VERSION 5.7 ;
BUSBITCHARS "[]" ;
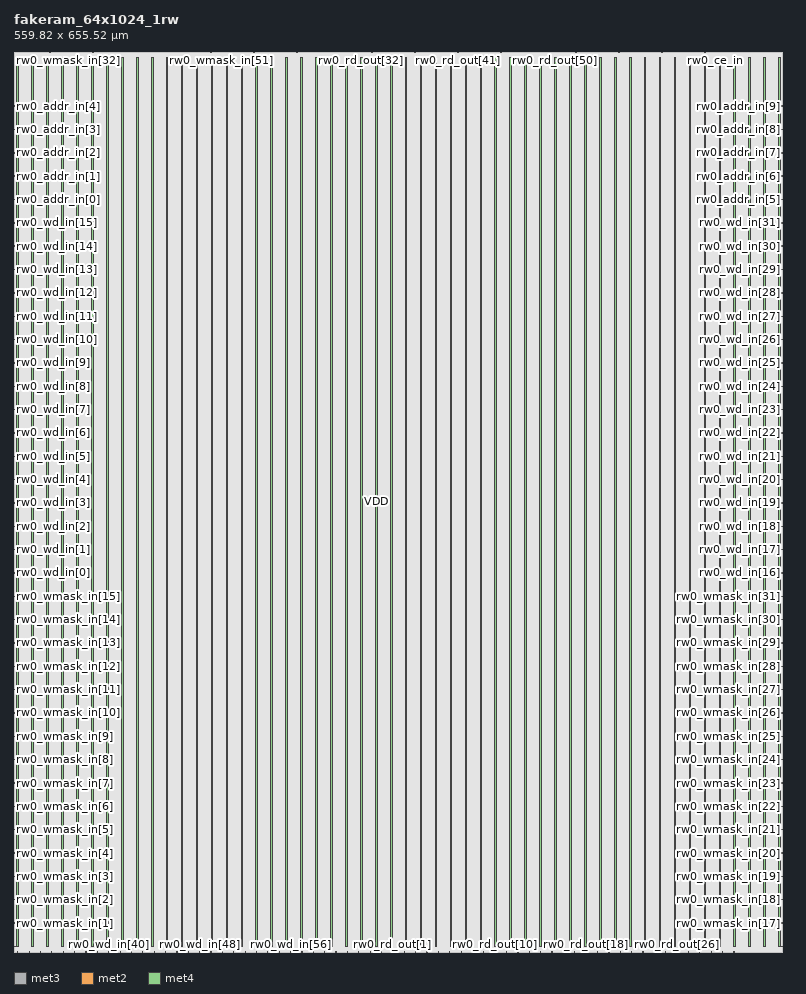
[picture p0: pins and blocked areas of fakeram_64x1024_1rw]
MACRO fakeram_64x1024_1rw
  FOREIGN fakeram_64x1024_1rw 0 0 ;
  SYMMETRY X Y R90 ;
  SIZE 559.820 BY 655.520 ;
  CLASS BLOCK ;
  PIN rw0_wmask_in[0]
    DIRECTION INPUT ;
    USE SIGNAL ;
    SHAPE ABUTMENT ;
    PORT
      LAYER met3 ;
      RECT 0.000 3.930 0.900 4.230 ;
    END
  END rw0_wmask_in[0]
  PIN rw0_wmask_in[1]
    DIRECTION INPUT ;
    USE SIGNAL ;
    SHAPE ABUTMENT ;
    PORT
      LAYER met3 ;
      RECT 0.000 20.930 0.900 21.230 ;
    END
  END rw0_wmask_in[1]
  PIN rw0_wmask_in[2]
    DIRECTION INPUT ;
    USE SIGNAL ;
    SHAPE ABUTMENT ;
    PORT
      LAYER met3 ;
      RECT 0.000 37.930 0.900 38.230 ;
    END
  END rw0_wmask_in[2]
  PIN rw0_wmask_in[3]
    DIRECTION INPUT ;
    USE SIGNAL ;
    SHAPE ABUTMENT ;
    PORT
      LAYER met3 ;
      RECT 0.000 54.930 0.900 55.230 ;
    END
  END rw0_wmask_in[3]
  PIN rw0_wmask_in[4]
    DIRECTION INPUT ;
    USE SIGNAL ;
    SHAPE ABUTMENT ;
    PORT
      LAYER met3 ;
      RECT 0.000 71.930 0.900 72.230 ;
    END
  END rw0_wmask_in[4]
  PIN rw0_wmask_in[5]
    DIRECTION INPUT ;
    USE SIGNAL ;
    SHAPE ABUTMENT ;
    PORT
      LAYER met3 ;
      RECT 0.000 88.930 0.900 89.230 ;
    END
  END rw0_wmask_in[5]
  PIN rw0_wmask_in[6]
    DIRECTION INPUT ;
    USE SIGNAL ;
    SHAPE ABUTMENT ;
    PORT
      LAYER met3 ;
      RECT 0.000 105.930 0.900 106.230 ;
    END
  END rw0_wmask_in[6]
  PIN rw0_wmask_in[7]
    DIRECTION INPUT ;
    USE SIGNAL ;
    SHAPE ABUTMENT ;
    PORT
      LAYER met3 ;
      RECT 0.000 122.930 0.900 123.230 ;
    END
  END rw0_wmask_in[7]
  PIN rw0_wmask_in[8]
    DIRECTION INPUT ;
    USE SIGNAL ;
    SHAPE ABUTMENT ;
    PORT
      LAYER met3 ;
      RECT 0.000 139.930 0.900 140.230 ;
    END
  END rw0_wmask_in[8]
  PIN rw0_wmask_in[9]
    DIRECTION INPUT ;
    USE SIGNAL ;
    SHAPE ABUTMENT ;
    PORT
      LAYER met3 ;
      RECT 0.000 156.930 0.900 157.230 ;
    END
  END rw0_wmask_in[9]
  PIN rw0_wmask_in[10]
    DIRECTION INPUT ;
    USE SIGNAL ;
    SHAPE ABUTMENT ;
    PORT
      LAYER met3 ;
      RECT 0.000 173.930 0.900 174.230 ;
    END
  END rw0_wmask_in[10]
  PIN rw0_wmask_in[11]
    DIRECTION INPUT ;
    USE SIGNAL ;
    SHAPE ABUTMENT ;
    PORT
      LAYER met3 ;
      RECT 0.000 190.930 0.900 191.230 ;
    END
  END rw0_wmask_in[11]
  PIN rw0_wmask_in[12]
    DIRECTION INPUT ;
    USE SIGNAL ;
    SHAPE ABUTMENT ;
    PORT
      LAYER met3 ;
      RECT 0.000 207.930 0.900 208.230 ;
    END
  END rw0_wmask_in[12]
  PIN rw0_wmask_in[13]
    DIRECTION INPUT ;
    USE SIGNAL ;
    SHAPE ABUTMENT ;
    PORT
      LAYER met3 ;
      RECT 0.000 224.930 0.900 225.230 ;
    END
  END rw0_wmask_in[13]
  PIN rw0_wmask_in[14]
    DIRECTION INPUT ;
    USE SIGNAL ;
    SHAPE ABUTMENT ;
    PORT
      LAYER met3 ;
      RECT 0.000 241.930 0.900 242.230 ;
    END
  END rw0_wmask_in[14]
  PIN rw0_wmask_in[15]
    DIRECTION INPUT ;
    USE SIGNAL ;
    SHAPE ABUTMENT ;
    PORT
      LAYER met3 ;
      RECT 0.000 258.930 0.900 259.230 ;
    END
  END rw0_wmask_in[15]
  PIN rw0_wmask_in[16]
    DIRECTION INPUT ;
    USE SIGNAL ;
    SHAPE ABUTMENT ;
    PORT
      LAYER met3 ;
      RECT 558.920 3.930 559.820 4.230 ;
    END
  END rw0_wmask_in[16]
  PIN rw0_wmask_in[17]
    DIRECTION INPUT ;
    USE SIGNAL ;
    SHAPE ABUTMENT ;
    PORT
      LAYER met3 ;
      RECT 558.920 20.930 559.820 21.230 ;
    END
  END rw0_wmask_in[17]
  PIN rw0_wmask_in[18]
    DIRECTION INPUT ;
    USE SIGNAL ;
    SHAPE ABUTMENT ;
    PORT
      LAYER met3 ;
      RECT 558.920 37.930 559.820 38.230 ;
    END
  END rw0_wmask_in[18]
  PIN rw0_wmask_in[19]
    DIRECTION INPUT ;
    USE SIGNAL ;
    SHAPE ABUTMENT ;
    PORT
      LAYER met3 ;
      RECT 558.920 54.930 559.820 55.230 ;
    END
  END rw0_wmask_in[19]
  PIN rw0_wmask_in[20]
    DIRECTION INPUT ;
    USE SIGNAL ;
    SHAPE ABUTMENT ;
    PORT
      LAYER met3 ;
      RECT 558.920 71.930 559.820 72.230 ;
    END
  END rw0_wmask_in[20]
  PIN rw0_wmask_in[21]
    DIRECTION INPUT ;
    USE SIGNAL ;
    SHAPE ABUTMENT ;
    PORT
      LAYER met3 ;
      RECT 558.920 88.930 559.820 89.230 ;
    END
  END rw0_wmask_in[21]
  PIN rw0_wmask_in[22]
    DIRECTION INPUT ;
    USE SIGNAL ;
    SHAPE ABUTMENT ;
    PORT
      LAYER met3 ;
      RECT 558.920 105.930 559.820 106.230 ;
    END
  END rw0_wmask_in[22]
  PIN rw0_wmask_in[23]
    DIRECTION INPUT ;
    USE SIGNAL ;
    SHAPE ABUTMENT ;
    PORT
      LAYER met3 ;
      RECT 558.920 122.930 559.820 123.230 ;
    END
  END rw0_wmask_in[23]
  PIN rw0_wmask_in[24]
    DIRECTION INPUT ;
    USE SIGNAL ;
    SHAPE ABUTMENT ;
    PORT
      LAYER met3 ;
      RECT 558.920 139.930 559.820 140.230 ;
    END
  END rw0_wmask_in[24]
  PIN rw0_wmask_in[25]
    DIRECTION INPUT ;
    USE SIGNAL ;
    SHAPE ABUTMENT ;
    PORT
      LAYER met3 ;
      RECT 558.920 156.930 559.820 157.230 ;
    END
  END rw0_wmask_in[25]
  PIN rw0_wmask_in[26]
    DIRECTION INPUT ;
    USE SIGNAL ;
    SHAPE ABUTMENT ;
    PORT
      LAYER met3 ;
      RECT 558.920 173.930 559.820 174.230 ;
    END
  END rw0_wmask_in[26]
  PIN rw0_wmask_in[27]
    DIRECTION INPUT ;
    USE SIGNAL ;
    SHAPE ABUTMENT ;
    PORT
      LAYER met3 ;
      RECT 558.920 190.930 559.820 191.230 ;
    END
  END rw0_wmask_in[27]
  PIN rw0_wmask_in[28]
    DIRECTION INPUT ;
    USE SIGNAL ;
    SHAPE ABUTMENT ;
    PORT
      LAYER met3 ;
      RECT 558.920 207.930 559.820 208.230 ;
    END
  END rw0_wmask_in[28]
  PIN rw0_wmask_in[29]
    DIRECTION INPUT ;
    USE SIGNAL ;
    SHAPE ABUTMENT ;
    PORT
      LAYER met3 ;
      RECT 558.920 224.930 559.820 225.230 ;
    END
  END rw0_wmask_in[29]
  PIN rw0_wmask_in[30]
    DIRECTION INPUT ;
    USE SIGNAL ;
    SHAPE ABUTMENT ;
    PORT
      LAYER met3 ;
      RECT 558.920 241.930 559.820 242.230 ;
    END
  END rw0_wmask_in[30]
  PIN rw0_wmask_in[31]
    DIRECTION INPUT ;
    USE SIGNAL ;
    SHAPE ABUTMENT ;
    PORT
      LAYER met3 ;
      RECT 558.920 258.930 559.820 259.230 ;
    END
  END rw0_wmask_in[31]
  PIN rw0_wmask_in[32]
    DIRECTION INPUT ;
    USE SIGNAL ;
    SHAPE ABUTMENT ;
    PORT
      LAYER met2 ;
      RECT 2.690 655.100 2.830 655.520 ;
    END
  END rw0_wmask_in[32]
  PIN rw0_wmask_in[33]
    DIRECTION INPUT ;
    USE SIGNAL ;
    SHAPE ABUTMENT ;
    PORT
      LAYER met2 ;
      RECT 10.510 655.100 10.650 655.520 ;
    END
  END rw0_wmask_in[33]
  PIN rw0_wmask_in[34]
    DIRECTION INPUT ;
    USE SIGNAL ;
    SHAPE ABUTMENT ;
    PORT
      LAYER met2 ;
      RECT 18.330 655.100 18.470 655.520 ;
    END
  END rw0_wmask_in[34]
  PIN rw0_wmask_in[35]
    DIRECTION INPUT ;
    USE SIGNAL ;
    SHAPE ABUTMENT ;
    PORT
      LAYER met2 ;
      RECT 26.150 655.100 26.290 655.520 ;
    END
  END rw0_wmask_in[35]
  PIN rw0_wmask_in[36]
    DIRECTION INPUT ;
    USE SIGNAL ;
    SHAPE ABUTMENT ;
    PORT
      LAYER met2 ;
      RECT 33.970 655.100 34.110 655.520 ;
    END
  END rw0_wmask_in[36]
  PIN rw0_wmask_in[37]
    DIRECTION INPUT ;
    USE SIGNAL ;
    SHAPE ABUTMENT ;
    PORT
      LAYER met2 ;
      RECT 41.790 655.100 41.930 655.520 ;
    END
  END rw0_wmask_in[37]
  PIN rw0_wmask_in[38]
    DIRECTION INPUT ;
    USE SIGNAL ;
    SHAPE ABUTMENT ;
    PORT
      LAYER met2 ;
      RECT 49.610 655.100 49.750 655.520 ;
    END
  END rw0_wmask_in[38]
  PIN rw0_wmask_in[39]
    DIRECTION INPUT ;
    USE SIGNAL ;
    SHAPE ABUTMENT ;
    PORT
      LAYER met2 ;
      RECT 57.430 655.100 57.570 655.520 ;
    END
  END rw0_wmask_in[39]
  PIN rw0_wmask_in[40]
    DIRECTION INPUT ;
    USE SIGNAL ;
    SHAPE ABUTMENT ;
    PORT
      LAYER met2 ;
      RECT 65.250 655.100 65.390 655.520 ;
    END
  END rw0_wmask_in[40]
  PIN rw0_wmask_in[41]
    DIRECTION INPUT ;
    USE SIGNAL ;
    SHAPE ABUTMENT ;
    PORT
      LAYER met2 ;
      RECT 73.070 655.100 73.210 655.520 ;
    END
  END rw0_wmask_in[41]
  PIN rw0_wmask_in[42]
    DIRECTION INPUT ;
    USE SIGNAL ;
    SHAPE ABUTMENT ;
    PORT
      LAYER met2 ;
      RECT 80.890 655.100 81.030 655.520 ;
    END
  END rw0_wmask_in[42]
  PIN rw0_wmask_in[43]
    DIRECTION INPUT ;
    USE SIGNAL ;
    SHAPE ABUTMENT ;
    PORT
      LAYER met2 ;
      RECT 88.710 655.100 88.850 655.520 ;
    END
  END rw0_wmask_in[43]
  PIN rw0_wmask_in[44]
    DIRECTION INPUT ;
    USE SIGNAL ;
    SHAPE ABUTMENT ;
    PORT
      LAYER met2 ;
      RECT 96.530 655.100 96.670 655.520 ;
    END
  END rw0_wmask_in[44]
  PIN rw0_wmask_in[45]
    DIRECTION INPUT ;
    USE SIGNAL ;
    SHAPE ABUTMENT ;
    PORT
      LAYER met2 ;
      RECT 104.350 655.100 104.490 655.520 ;
    END
  END rw0_wmask_in[45]
  PIN rw0_wmask_in[46]
    DIRECTION INPUT ;
    USE SIGNAL ;
    SHAPE ABUTMENT ;
    PORT
      LAYER met2 ;
      RECT 112.170 655.100 112.310 655.520 ;
    END
  END rw0_wmask_in[46]
  PIN rw0_wmask_in[47]
    DIRECTION INPUT ;
    USE SIGNAL ;
    SHAPE ABUTMENT ;
    PORT
      LAYER met2 ;
      RECT 119.990 655.100 120.130 655.520 ;
    END
  END rw0_wmask_in[47]
  PIN rw0_wmask_in[48]
    DIRECTION INPUT ;
    USE SIGNAL ;
    SHAPE ABUTMENT ;
    PORT
      LAYER met2 ;
      RECT 127.810 655.100 127.950 655.520 ;
    END
  END rw0_wmask_in[48]
  PIN rw0_wmask_in[49]
    DIRECTION INPUT ;
    USE SIGNAL ;
    SHAPE ABUTMENT ;
    PORT
      LAYER met2 ;
      RECT 135.630 655.100 135.770 655.520 ;
    END
  END rw0_wmask_in[49]
  PIN rw0_wmask_in[50]
    DIRECTION INPUT ;
    USE SIGNAL ;
    SHAPE ABUTMENT ;
    PORT
      LAYER met2 ;
      RECT 143.450 655.100 143.590 655.520 ;
    END
  END rw0_wmask_in[50]
  PIN rw0_wmask_in[51]
    DIRECTION INPUT ;
    USE SIGNAL ;
    SHAPE ABUTMENT ;
    PORT
      LAYER met2 ;
      RECT 151.270 655.100 151.410 655.520 ;
    END
  END rw0_wmask_in[51]
  PIN rw0_wmask_in[52]
    DIRECTION INPUT ;
    USE SIGNAL ;
    SHAPE ABUTMENT ;
    PORT
      LAYER met2 ;
      RECT 159.090 655.100 159.230 655.520 ;
    END
  END rw0_wmask_in[52]
  PIN rw0_wmask_in[53]
    DIRECTION INPUT ;
    USE SIGNAL ;
    SHAPE ABUTMENT ;
    PORT
      LAYER met2 ;
      RECT 166.910 655.100 167.050 655.520 ;
    END
  END rw0_wmask_in[53]
  PIN rw0_wmask_in[54]
    DIRECTION INPUT ;
    USE SIGNAL ;
    SHAPE ABUTMENT ;
    PORT
      LAYER met2 ;
      RECT 174.730 655.100 174.870 655.520 ;
    END
  END rw0_wmask_in[54]
  PIN rw0_wmask_in[55]
    DIRECTION INPUT ;
    USE SIGNAL ;
    SHAPE ABUTMENT ;
    PORT
      LAYER met2 ;
      RECT 182.550 655.100 182.690 655.520 ;
    END
  END rw0_wmask_in[55]
  PIN rw0_wmask_in[56]
    DIRECTION INPUT ;
    USE SIGNAL ;
    SHAPE ABUTMENT ;
    PORT
      LAYER met2 ;
      RECT 190.370 655.100 190.510 655.520 ;
    END
  END rw0_wmask_in[56]
  PIN rw0_wmask_in[57]
    DIRECTION INPUT ;
    USE SIGNAL ;
    SHAPE ABUTMENT ;
    PORT
      LAYER met2 ;
      RECT 198.190 655.100 198.330 655.520 ;
    END
  END rw0_wmask_in[57]
  PIN rw0_wmask_in[58]
    DIRECTION INPUT ;
    USE SIGNAL ;
    SHAPE ABUTMENT ;
    PORT
      LAYER met2 ;
      RECT 206.010 655.100 206.150 655.520 ;
    END
  END rw0_wmask_in[58]
  PIN rw0_wmask_in[59]
    DIRECTION INPUT ;
    USE SIGNAL ;
    SHAPE ABUTMENT ;
    PORT
      LAYER met2 ;
      RECT 213.830 655.100 213.970 655.520 ;
    END
  END rw0_wmask_in[59]
  PIN rw0_wmask_in[60]
    DIRECTION INPUT ;
    USE SIGNAL ;
    SHAPE ABUTMENT ;
    PORT
      LAYER met2 ;
      RECT 221.650 655.100 221.790 655.520 ;
    END
  END rw0_wmask_in[60]
  PIN rw0_wmask_in[61]
    DIRECTION INPUT ;
    USE SIGNAL ;
    SHAPE ABUTMENT ;
    PORT
      LAYER met2 ;
      RECT 229.470 655.100 229.610 655.520 ;
    END
  END rw0_wmask_in[61]
  PIN rw0_wmask_in[62]
    DIRECTION INPUT ;
    USE SIGNAL ;
    SHAPE ABUTMENT ;
    PORT
      LAYER met2 ;
      RECT 237.290 655.100 237.430 655.520 ;
    END
  END rw0_wmask_in[62]
  PIN rw0_wmask_in[63]
    DIRECTION INPUT ;
    USE SIGNAL ;
    SHAPE ABUTMENT ;
    PORT
      LAYER met2 ;
      RECT 245.110 655.100 245.250 655.520 ;
    END
  END rw0_wmask_in[63]
  PIN rw0_wd_in[0]
    DIRECTION INPUT ;
    USE SIGNAL ;
    SHAPE ABUTMENT ;
    PORT
      LAYER met3 ;
      RECT 0.000 275.930 0.900 276.230 ;
    END
  END rw0_wd_in[0]
  PIN rw0_wd_in[1]
    DIRECTION INPUT ;
    USE SIGNAL ;
    SHAPE ABUTMENT ;
    PORT
      LAYER met3 ;
      RECT 0.000 292.930 0.900 293.230 ;
    END
  END rw0_wd_in[1]
  PIN rw0_wd_in[2]
    DIRECTION INPUT ;
    USE SIGNAL ;
    SHAPE ABUTMENT ;
    PORT
      LAYER met3 ;
      RECT 0.000 309.930 0.900 310.230 ;
    END
  END rw0_wd_in[2]
  PIN rw0_wd_in[3]
    DIRECTION INPUT ;
    USE SIGNAL ;
    SHAPE ABUTMENT ;
    PORT
      LAYER met3 ;
      RECT 0.000 326.930 0.900 327.230 ;
    END
  END rw0_wd_in[3]
  PIN rw0_wd_in[4]
    DIRECTION INPUT ;
    USE SIGNAL ;
    SHAPE ABUTMENT ;
    PORT
      LAYER met3 ;
      RECT 0.000 343.930 0.900 344.230 ;
    END
  END rw0_wd_in[4]
  PIN rw0_wd_in[5]
    DIRECTION INPUT ;
    USE SIGNAL ;
    SHAPE ABUTMENT ;
    PORT
      LAYER met3 ;
      RECT 0.000 360.930 0.900 361.230 ;
    END
  END rw0_wd_in[5]
  PIN rw0_wd_in[6]
    DIRECTION INPUT ;
    USE SIGNAL ;
    SHAPE ABUTMENT ;
    PORT
      LAYER met3 ;
      RECT 0.000 377.930 0.900 378.230 ;
    END
  END rw0_wd_in[6]
  PIN rw0_wd_in[7]
    DIRECTION INPUT ;
    USE SIGNAL ;
    SHAPE ABUTMENT ;
    PORT
      LAYER met3 ;
      RECT 0.000 394.930 0.900 395.230 ;
    END
  END rw0_wd_in[7]
  PIN rw0_wd_in[8]
    DIRECTION INPUT ;
    USE SIGNAL ;
    SHAPE ABUTMENT ;
    PORT
      LAYER met3 ;
      RECT 0.000 411.930 0.900 412.230 ;
    END
  END rw0_wd_in[8]
  PIN rw0_wd_in[9]
    DIRECTION INPUT ;
    USE SIGNAL ;
    SHAPE ABUTMENT ;
    PORT
      LAYER met3 ;
      RECT 0.000 428.930 0.900 429.230 ;
    END
  END rw0_wd_in[9]
  PIN rw0_wd_in[10]
    DIRECTION INPUT ;
    USE SIGNAL ;
    SHAPE ABUTMENT ;
    PORT
      LAYER met3 ;
      RECT 0.000 445.930 0.900 446.230 ;
    END
  END rw0_wd_in[10]
  PIN rw0_wd_in[11]
    DIRECTION INPUT ;
    USE SIGNAL ;
    SHAPE ABUTMENT ;
    PORT
      LAYER met3 ;
      RECT 0.000 462.930 0.900 463.230 ;
    END
  END rw0_wd_in[11]
  PIN rw0_wd_in[12]
    DIRECTION INPUT ;
    USE SIGNAL ;
    SHAPE ABUTMENT ;
    PORT
      LAYER met3 ;
      RECT 0.000 479.930 0.900 480.230 ;
    END
  END rw0_wd_in[12]
  PIN rw0_wd_in[13]
    DIRECTION INPUT ;
    USE SIGNAL ;
    SHAPE ABUTMENT ;
    PORT
      LAYER met3 ;
      RECT 0.000 496.930 0.900 497.230 ;
    END
  END rw0_wd_in[13]
  PIN rw0_wd_in[14]
    DIRECTION INPUT ;
    USE SIGNAL ;
    SHAPE ABUTMENT ;
    PORT
      LAYER met3 ;
      RECT 0.000 513.930 0.900 514.230 ;
    END
  END rw0_wd_in[14]
  PIN rw0_wd_in[15]
    DIRECTION INPUT ;
    USE SIGNAL ;
    SHAPE ABUTMENT ;
    PORT
      LAYER met3 ;
      RECT 0.000 530.930 0.900 531.230 ;
    END
  END rw0_wd_in[15]
  PIN rw0_wd_in[16]
    DIRECTION INPUT ;
    USE SIGNAL ;
    SHAPE ABUTMENT ;
    PORT
      LAYER met3 ;
      RECT 558.920 275.930 559.820 276.230 ;
    END
  END rw0_wd_in[16]
  PIN rw0_wd_in[17]
    DIRECTION INPUT ;
    USE SIGNAL ;
    SHAPE ABUTMENT ;
    PORT
      LAYER met3 ;
      RECT 558.920 292.930 559.820 293.230 ;
    END
  END rw0_wd_in[17]
  PIN rw0_wd_in[18]
    DIRECTION INPUT ;
    USE SIGNAL ;
    SHAPE ABUTMENT ;
    PORT
      LAYER met3 ;
      RECT 558.920 309.930 559.820 310.230 ;
    END
  END rw0_wd_in[18]
  PIN rw0_wd_in[19]
    DIRECTION INPUT ;
    USE SIGNAL ;
    SHAPE ABUTMENT ;
    PORT
      LAYER met3 ;
      RECT 558.920 326.930 559.820 327.230 ;
    END
  END rw0_wd_in[19]
  PIN rw0_wd_in[20]
    DIRECTION INPUT ;
    USE SIGNAL ;
    SHAPE ABUTMENT ;
    PORT
      LAYER met3 ;
      RECT 558.920 343.930 559.820 344.230 ;
    END
  END rw0_wd_in[20]
  PIN rw0_wd_in[21]
    DIRECTION INPUT ;
    USE SIGNAL ;
    SHAPE ABUTMENT ;
    PORT
      LAYER met3 ;
      RECT 558.920 360.930 559.820 361.230 ;
    END
  END rw0_wd_in[21]
  PIN rw0_wd_in[22]
    DIRECTION INPUT ;
    USE SIGNAL ;
    SHAPE ABUTMENT ;
    PORT
      LAYER met3 ;
      RECT 558.920 377.930 559.820 378.230 ;
    END
  END rw0_wd_in[22]
  PIN rw0_wd_in[23]
    DIRECTION INPUT ;
    USE SIGNAL ;
    SHAPE ABUTMENT ;
    PORT
      LAYER met3 ;
      RECT 558.920 394.930 559.820 395.230 ;
    END
  END rw0_wd_in[23]
  PIN rw0_wd_in[24]
    DIRECTION INPUT ;
    USE SIGNAL ;
    SHAPE ABUTMENT ;
    PORT
      LAYER met3 ;
      RECT 558.920 411.930 559.820 412.230 ;
    END
  END rw0_wd_in[24]
  PIN rw0_wd_in[25]
    DIRECTION INPUT ;
    USE SIGNAL ;
    SHAPE ABUTMENT ;
    PORT
      LAYER met3 ;
      RECT 558.920 428.930 559.820 429.230 ;
    END
  END rw0_wd_in[25]
  PIN rw0_wd_in[26]
    DIRECTION INPUT ;
    USE SIGNAL ;
    SHAPE ABUTMENT ;
    PORT
      LAYER met3 ;
      RECT 558.920 445.930 559.820 446.230 ;
    END
  END rw0_wd_in[26]
  PIN rw0_wd_in[27]
    DIRECTION INPUT ;
    USE SIGNAL ;
    SHAPE ABUTMENT ;
    PORT
      LAYER met3 ;
      RECT 558.920 462.930 559.820 463.230 ;
    END
  END rw0_wd_in[27]
  PIN rw0_wd_in[28]
    DIRECTION INPUT ;
    USE SIGNAL ;
    SHAPE ABUTMENT ;
    PORT
      LAYER met3 ;
      RECT 558.920 479.930 559.820 480.230 ;
    END
  END rw0_wd_in[28]
  PIN rw0_wd_in[29]
    DIRECTION INPUT ;
    USE SIGNAL ;
    SHAPE ABUTMENT ;
    PORT
      LAYER met3 ;
      RECT 558.920 496.930 559.820 497.230 ;
    END
  END rw0_wd_in[29]
  PIN rw0_wd_in[30]
    DIRECTION INPUT ;
    USE SIGNAL ;
    SHAPE ABUTMENT ;
    PORT
      LAYER met3 ;
      RECT 558.920 513.930 559.820 514.230 ;
    END
  END rw0_wd_in[30]
  PIN rw0_wd_in[31]
    DIRECTION INPUT ;
    USE SIGNAL ;
    SHAPE ABUTMENT ;
    PORT
      LAYER met3 ;
      RECT 558.920 530.930 559.820 531.230 ;
    END
  END rw0_wd_in[31]
  PIN rw0_wd_in[32]
    DIRECTION OUTPUT ;
    USE SIGNAL ;
    SHAPE ABUTMENT ;
    PORT
      LAYER met2 ;
      RECT 2.690 0.000 2.830 0.420 ;
    END
  END rw0_wd_in[32]
  PIN rw0_wd_in[33]
    DIRECTION OUTPUT ;
    USE SIGNAL ;
    SHAPE ABUTMENT ;
    PORT
      LAYER met2 ;
      RECT 10.970 0.000 11.110 0.420 ;
    END
  END rw0_wd_in[33]
  PIN rw0_wd_in[34]
    DIRECTION OUTPUT ;
    USE SIGNAL ;
    SHAPE ABUTMENT ;
    PORT
      LAYER met2 ;
      RECT 19.250 0.000 19.390 0.420 ;
    END
  END rw0_wd_in[34]
  PIN rw0_wd_in[35]
    DIRECTION OUTPUT ;
    USE SIGNAL ;
    SHAPE ABUTMENT ;
    PORT
      LAYER met2 ;
      RECT 27.530 0.000 27.670 0.420 ;
    END
  END rw0_wd_in[35]
  PIN rw0_wd_in[36]
    DIRECTION OUTPUT ;
    USE SIGNAL ;
    SHAPE ABUTMENT ;
    PORT
      LAYER met2 ;
      RECT 35.810 0.000 35.950 0.420 ;
    END
  END rw0_wd_in[36]
  PIN rw0_wd_in[37]
    DIRECTION OUTPUT ;
    USE SIGNAL ;
    SHAPE ABUTMENT ;
    PORT
      LAYER met2 ;
      RECT 44.090 0.000 44.230 0.420 ;
    END
  END rw0_wd_in[37]
  PIN rw0_wd_in[38]
    DIRECTION OUTPUT ;
    USE SIGNAL ;
    SHAPE ABUTMENT ;
    PORT
      LAYER met2 ;
      RECT 52.370 0.000 52.510 0.420 ;
    END
  END rw0_wd_in[38]
  PIN rw0_wd_in[39]
    DIRECTION OUTPUT ;
    USE SIGNAL ;
    SHAPE ABUTMENT ;
    PORT
      LAYER met2 ;
      RECT 60.650 0.000 60.790 0.420 ;
    END
  END rw0_wd_in[39]
  PIN rw0_wd_in[40]
    DIRECTION OUTPUT ;
    USE SIGNAL ;
    SHAPE ABUTMENT ;
    PORT
      LAYER met2 ;
      RECT 68.930 0.000 69.070 0.420 ;
    END
  END rw0_wd_in[40]
  PIN rw0_wd_in[41]
    DIRECTION OUTPUT ;
    USE SIGNAL ;
    SHAPE ABUTMENT ;
    PORT
      LAYER met2 ;
      RECT 77.210 0.000 77.350 0.420 ;
    END
  END rw0_wd_in[41]
  PIN rw0_wd_in[42]
    DIRECTION OUTPUT ;
    USE SIGNAL ;
    SHAPE ABUTMENT ;
    PORT
      LAYER met2 ;
      RECT 85.490 0.000 85.630 0.420 ;
    END
  END rw0_wd_in[42]
  PIN rw0_wd_in[43]
    DIRECTION OUTPUT ;
    USE SIGNAL ;
    SHAPE ABUTMENT ;
    PORT
      LAYER met2 ;
      RECT 93.770 0.000 93.910 0.420 ;
    END
  END rw0_wd_in[43]
  PIN rw0_wd_in[44]
    DIRECTION OUTPUT ;
    USE SIGNAL ;
    SHAPE ABUTMENT ;
    PORT
      LAYER met2 ;
      RECT 102.050 0.000 102.190 0.420 ;
    END
  END rw0_wd_in[44]
  PIN rw0_wd_in[45]
    DIRECTION OUTPUT ;
    USE SIGNAL ;
    SHAPE ABUTMENT ;
    PORT
      LAYER met2 ;
      RECT 110.330 0.000 110.470 0.420 ;
    END
  END rw0_wd_in[45]
  PIN rw0_wd_in[46]
    DIRECTION OUTPUT ;
    USE SIGNAL ;
    SHAPE ABUTMENT ;
    PORT
      LAYER met2 ;
      RECT 118.610 0.000 118.750 0.420 ;
    END
  END rw0_wd_in[46]
  PIN rw0_wd_in[47]
    DIRECTION OUTPUT ;
    USE SIGNAL ;
    SHAPE ABUTMENT ;
    PORT
      LAYER met2 ;
      RECT 126.890 0.000 127.030 0.420 ;
    END
  END rw0_wd_in[47]
  PIN rw0_wd_in[48]
    DIRECTION OUTPUT ;
    USE SIGNAL ;
    SHAPE ABUTMENT ;
    PORT
      LAYER met2 ;
      RECT 135.170 0.000 135.310 0.420 ;
    END
  END rw0_wd_in[48]
  PIN rw0_wd_in[49]
    DIRECTION OUTPUT ;
    USE SIGNAL ;
    SHAPE ABUTMENT ;
    PORT
      LAYER met2 ;
      RECT 143.450 0.000 143.590 0.420 ;
    END
  END rw0_wd_in[49]
  PIN rw0_wd_in[50]
    DIRECTION OUTPUT ;
    USE SIGNAL ;
    SHAPE ABUTMENT ;
    PORT
      LAYER met2 ;
      RECT 151.730 0.000 151.870 0.420 ;
    END
  END rw0_wd_in[50]
  PIN rw0_wd_in[51]
    DIRECTION OUTPUT ;
    USE SIGNAL ;
    SHAPE ABUTMENT ;
    PORT
      LAYER met2 ;
      RECT 160.010 0.000 160.150 0.420 ;
    END
  END rw0_wd_in[51]
  PIN rw0_wd_in[52]
    DIRECTION OUTPUT ;
    USE SIGNAL ;
    SHAPE ABUTMENT ;
    PORT
      LAYER met2 ;
      RECT 168.290 0.000 168.430 0.420 ;
    END
  END rw0_wd_in[52]
  PIN rw0_wd_in[53]
    DIRECTION OUTPUT ;
    USE SIGNAL ;
    SHAPE ABUTMENT ;
    PORT
      LAYER met2 ;
      RECT 176.570 0.000 176.710 0.420 ;
    END
  END rw0_wd_in[53]
  PIN rw0_wd_in[54]
    DIRECTION OUTPUT ;
    USE SIGNAL ;
    SHAPE ABUTMENT ;
    PORT
      LAYER met2 ;
      RECT 184.850 0.000 184.990 0.420 ;
    END
  END rw0_wd_in[54]
  PIN rw0_wd_in[55]
    DIRECTION OUTPUT ;
    USE SIGNAL ;
    SHAPE ABUTMENT ;
    PORT
      LAYER met2 ;
      RECT 193.130 0.000 193.270 0.420 ;
    END
  END rw0_wd_in[55]
  PIN rw0_wd_in[56]
    DIRECTION OUTPUT ;
    USE SIGNAL ;
    SHAPE ABUTMENT ;
    PORT
      LAYER met2 ;
      RECT 201.410 0.000 201.550 0.420 ;
    END
  END rw0_wd_in[56]
  PIN rw0_wd_in[57]
    DIRECTION OUTPUT ;
    USE SIGNAL ;
    SHAPE ABUTMENT ;
    PORT
      LAYER met2 ;
      RECT 209.690 0.000 209.830 0.420 ;
    END
  END rw0_wd_in[57]
  PIN rw0_wd_in[58]
    DIRECTION OUTPUT ;
    USE SIGNAL ;
    SHAPE ABUTMENT ;
    PORT
      LAYER met2 ;
      RECT 217.970 0.000 218.110 0.420 ;
    END
  END rw0_wd_in[58]
  PIN rw0_wd_in[59]
    DIRECTION OUTPUT ;
    USE SIGNAL ;
    SHAPE ABUTMENT ;
    PORT
      LAYER met2 ;
      RECT 226.250 0.000 226.390 0.420 ;
    END
  END rw0_wd_in[59]
  PIN rw0_wd_in[60]
    DIRECTION OUTPUT ;
    USE SIGNAL ;
    SHAPE ABUTMENT ;
    PORT
      LAYER met2 ;
      RECT 234.530 0.000 234.670 0.420 ;
    END
  END rw0_wd_in[60]
  PIN rw0_wd_in[61]
    DIRECTION OUTPUT ;
    USE SIGNAL ;
    SHAPE ABUTMENT ;
    PORT
      LAYER met2 ;
      RECT 242.810 0.000 242.950 0.420 ;
    END
  END rw0_wd_in[61]
  PIN rw0_wd_in[62]
    DIRECTION OUTPUT ;
    USE SIGNAL ;
    SHAPE ABUTMENT ;
    PORT
      LAYER met2 ;
      RECT 251.090 0.000 251.230 0.420 ;
    END
  END rw0_wd_in[62]
  PIN rw0_wd_in[63]
    DIRECTION OUTPUT ;
    USE SIGNAL ;
    SHAPE ABUTMENT ;
    PORT
      LAYER met2 ;
      RECT 259.370 0.000 259.510 0.420 ;
    END
  END rw0_wd_in[63]
  PIN rw0_rd_out[0]
    DIRECTION OUTPUT ;
    USE SIGNAL ;
    SHAPE ABUTMENT ;
    PORT
      LAYER met2 ;
      RECT 267.650 0.000 267.790 0.420 ;
    END
  END rw0_rd_out[0]
  PIN rw0_rd_out[1]
    DIRECTION OUTPUT ;
    USE SIGNAL ;
    SHAPE ABUTMENT ;
    PORT
      LAYER met2 ;
      RECT 275.930 0.000 276.070 0.420 ;
    END
  END rw0_rd_out[1]
  PIN rw0_rd_out[2]
    DIRECTION OUTPUT ;
    USE SIGNAL ;
    SHAPE ABUTMENT ;
    PORT
      LAYER met2 ;
      RECT 284.210 0.000 284.350 0.420 ;
    END
  END rw0_rd_out[2]
  PIN rw0_rd_out[3]
    DIRECTION OUTPUT ;
    USE SIGNAL ;
    SHAPE ABUTMENT ;
    PORT
      LAYER met2 ;
      RECT 292.490 0.000 292.630 0.420 ;
    END
  END rw0_rd_out[3]
  PIN rw0_rd_out[4]
    DIRECTION OUTPUT ;
    USE SIGNAL ;
    SHAPE ABUTMENT ;
    PORT
      LAYER met2 ;
      RECT 300.770 0.000 300.910 0.420 ;
    END
  END rw0_rd_out[4]
  PIN rw0_rd_out[5]
    DIRECTION OUTPUT ;
    USE SIGNAL ;
    SHAPE ABUTMENT ;
    PORT
      LAYER met2 ;
      RECT 309.050 0.000 309.190 0.420 ;
    END
  END rw0_rd_out[5]
  PIN rw0_rd_out[6]
    DIRECTION OUTPUT ;
    USE SIGNAL ;
    SHAPE ABUTMENT ;
    PORT
      LAYER met2 ;
      RECT 317.330 0.000 317.470 0.420 ;
    END
  END rw0_rd_out[6]
  PIN rw0_rd_out[7]
    DIRECTION OUTPUT ;
    USE SIGNAL ;
    SHAPE ABUTMENT ;
    PORT
      LAYER met2 ;
      RECT 325.610 0.000 325.750 0.420 ;
    END
  END rw0_rd_out[7]
  PIN rw0_rd_out[8]
    DIRECTION OUTPUT ;
    USE SIGNAL ;
    SHAPE ABUTMENT ;
    PORT
      LAYER met2 ;
      RECT 333.890 0.000 334.030 0.420 ;
    END
  END rw0_rd_out[8]
  PIN rw0_rd_out[9]
    DIRECTION OUTPUT ;
    USE SIGNAL ;
    SHAPE ABUTMENT ;
    PORT
      LAYER met2 ;
      RECT 342.170 0.000 342.310 0.420 ;
    END
  END rw0_rd_out[9]
  PIN rw0_rd_out[10]
    DIRECTION OUTPUT ;
    USE SIGNAL ;
    SHAPE ABUTMENT ;
    PORT
      LAYER met2 ;
      RECT 350.450 0.000 350.590 0.420 ;
    END
  END rw0_rd_out[10]
  PIN rw0_rd_out[11]
    DIRECTION OUTPUT ;
    USE SIGNAL ;
    SHAPE ABUTMENT ;
    PORT
      LAYER met2 ;
      RECT 358.730 0.000 358.870 0.420 ;
    END
  END rw0_rd_out[11]
  PIN rw0_rd_out[12]
    DIRECTION OUTPUT ;
    USE SIGNAL ;
    SHAPE ABUTMENT ;
    PORT
      LAYER met2 ;
      RECT 367.010 0.000 367.150 0.420 ;
    END
  END rw0_rd_out[12]
  PIN rw0_rd_out[13]
    DIRECTION OUTPUT ;
    USE SIGNAL ;
    SHAPE ABUTMENT ;
    PORT
      LAYER met2 ;
      RECT 375.290 0.000 375.430 0.420 ;
    END
  END rw0_rd_out[13]
  PIN rw0_rd_out[14]
    DIRECTION OUTPUT ;
    USE SIGNAL ;
    SHAPE ABUTMENT ;
    PORT
      LAYER met2 ;
      RECT 383.570 0.000 383.710 0.420 ;
    END
  END rw0_rd_out[14]
  PIN rw0_rd_out[15]
    DIRECTION OUTPUT ;
    USE SIGNAL ;
    SHAPE ABUTMENT ;
    PORT
      LAYER met2 ;
      RECT 391.850 0.000 391.990 0.420 ;
    END
  END rw0_rd_out[15]
  PIN rw0_rd_out[16]
    DIRECTION OUTPUT ;
    USE SIGNAL ;
    SHAPE ABUTMENT ;
    PORT
      LAYER met2 ;
      RECT 400.130 0.000 400.270 0.420 ;
    END
  END rw0_rd_out[16]
  PIN rw0_rd_out[17]
    DIRECTION OUTPUT ;
    USE SIGNAL ;
    SHAPE ABUTMENT ;
    PORT
      LAYER met2 ;
      RECT 408.410 0.000 408.550 0.420 ;
    END
  END rw0_rd_out[17]
  PIN rw0_rd_out[18]
    DIRECTION OUTPUT ;
    USE SIGNAL ;
    SHAPE ABUTMENT ;
    PORT
      LAYER met2 ;
      RECT 416.690 0.000 416.830 0.420 ;
    END
  END rw0_rd_out[18]
  PIN rw0_rd_out[19]
    DIRECTION OUTPUT ;
    USE SIGNAL ;
    SHAPE ABUTMENT ;
    PORT
      LAYER met2 ;
      RECT 424.970 0.000 425.110 0.420 ;
    END
  END rw0_rd_out[19]
  PIN rw0_rd_out[20]
    DIRECTION OUTPUT ;
    USE SIGNAL ;
    SHAPE ABUTMENT ;
    PORT
      LAYER met2 ;
      RECT 433.250 0.000 433.390 0.420 ;
    END
  END rw0_rd_out[20]
  PIN rw0_rd_out[21]
    DIRECTION OUTPUT ;
    USE SIGNAL ;
    SHAPE ABUTMENT ;
    PORT
      LAYER met2 ;
      RECT 441.530 0.000 441.670 0.420 ;
    END
  END rw0_rd_out[21]
  PIN rw0_rd_out[22]
    DIRECTION OUTPUT ;
    USE SIGNAL ;
    SHAPE ABUTMENT ;
    PORT
      LAYER met2 ;
      RECT 449.810 0.000 449.950 0.420 ;
    END
  END rw0_rd_out[22]
  PIN rw0_rd_out[23]
    DIRECTION OUTPUT ;
    USE SIGNAL ;
    SHAPE ABUTMENT ;
    PORT
      LAYER met2 ;
      RECT 458.090 0.000 458.230 0.420 ;
    END
  END rw0_rd_out[23]
  PIN rw0_rd_out[24]
    DIRECTION OUTPUT ;
    USE SIGNAL ;
    SHAPE ABUTMENT ;
    PORT
      LAYER met2 ;
      RECT 466.370 0.000 466.510 0.420 ;
    END
  END rw0_rd_out[24]
  PIN rw0_rd_out[25]
    DIRECTION OUTPUT ;
    USE SIGNAL ;
    SHAPE ABUTMENT ;
    PORT
      LAYER met2 ;
      RECT 474.650 0.000 474.790 0.420 ;
    END
  END rw0_rd_out[25]
  PIN rw0_rd_out[26]
    DIRECTION OUTPUT ;
    USE SIGNAL ;
    SHAPE ABUTMENT ;
    PORT
      LAYER met2 ;
      RECT 482.930 0.000 483.070 0.420 ;
    END
  END rw0_rd_out[26]
  PIN rw0_rd_out[27]
    DIRECTION OUTPUT ;
    USE SIGNAL ;
    SHAPE ABUTMENT ;
    PORT
      LAYER met2 ;
      RECT 491.210 0.000 491.350 0.420 ;
    END
  END rw0_rd_out[27]
  PIN rw0_rd_out[28]
    DIRECTION OUTPUT ;
    USE SIGNAL ;
    SHAPE ABUTMENT ;
    PORT
      LAYER met2 ;
      RECT 499.490 0.000 499.630 0.420 ;
    END
  END rw0_rd_out[28]
  PIN rw0_rd_out[29]
    DIRECTION OUTPUT ;
    USE SIGNAL ;
    SHAPE ABUTMENT ;
    PORT
      LAYER met2 ;
      RECT 507.770 0.000 507.910 0.420 ;
    END
  END rw0_rd_out[29]
  PIN rw0_rd_out[30]
    DIRECTION OUTPUT ;
    USE SIGNAL ;
    SHAPE ABUTMENT ;
    PORT
      LAYER met2 ;
      RECT 516.050 0.000 516.190 0.420 ;
    END
  END rw0_rd_out[30]
  PIN rw0_rd_out[31]
    DIRECTION OUTPUT ;
    USE SIGNAL ;
    SHAPE ABUTMENT ;
    PORT
      LAYER met2 ;
      RECT 524.330 0.000 524.470 0.420 ;
    END
  END rw0_rd_out[31]
  PIN rw0_rd_out[32]
    DIRECTION OUTPUT ;
    USE SIGNAL ;
    SHAPE ABUTMENT ;
    PORT
      LAYER met2 ;
      RECT 252.930 655.100 253.070 655.520 ;
    END
  END rw0_rd_out[32]
  PIN rw0_rd_out[33]
    DIRECTION OUTPUT ;
    USE SIGNAL ;
    SHAPE ABUTMENT ;
    PORT
      LAYER met2 ;
      RECT 260.750 655.100 260.890 655.520 ;
    END
  END rw0_rd_out[33]
  PIN rw0_rd_out[34]
    DIRECTION OUTPUT ;
    USE SIGNAL ;
    SHAPE ABUTMENT ;
    PORT
      LAYER met2 ;
      RECT 268.570 655.100 268.710 655.520 ;
    END
  END rw0_rd_out[34]
  PIN rw0_rd_out[35]
    DIRECTION OUTPUT ;
    USE SIGNAL ;
    SHAPE ABUTMENT ;
    PORT
      LAYER met2 ;
      RECT 276.390 655.100 276.530 655.520 ;
    END
  END rw0_rd_out[35]
  PIN rw0_rd_out[36]
    DIRECTION OUTPUT ;
    USE SIGNAL ;
    SHAPE ABUTMENT ;
    PORT
      LAYER met2 ;
      RECT 284.210 655.100 284.350 655.520 ;
    END
  END rw0_rd_out[36]
  PIN rw0_rd_out[37]
    DIRECTION OUTPUT ;
    USE SIGNAL ;
    SHAPE ABUTMENT ;
    PORT
      LAYER met2 ;
      RECT 292.030 655.100 292.170 655.520 ;
    END
  END rw0_rd_out[37]
  PIN rw0_rd_out[38]
    DIRECTION OUTPUT ;
    USE SIGNAL ;
    SHAPE ABUTMENT ;
    PORT
      LAYER met2 ;
      RECT 299.850 655.100 299.990 655.520 ;
    END
  END rw0_rd_out[38]
  PIN rw0_rd_out[39]
    DIRECTION OUTPUT ;
    USE SIGNAL ;
    SHAPE ABUTMENT ;
    PORT
      LAYER met2 ;
      RECT 307.670 655.100 307.810 655.520 ;
    END
  END rw0_rd_out[39]
  PIN rw0_rd_out[40]
    DIRECTION OUTPUT ;
    USE SIGNAL ;
    SHAPE ABUTMENT ;
    PORT
      LAYER met2 ;
      RECT 315.490 655.100 315.630 655.520 ;
    END
  END rw0_rd_out[40]
  PIN rw0_rd_out[41]
    DIRECTION OUTPUT ;
    USE SIGNAL ;
    SHAPE ABUTMENT ;
    PORT
      LAYER met2 ;
      RECT 323.310 655.100 323.450 655.520 ;
    END
  END rw0_rd_out[41]
  PIN rw0_rd_out[42]
    DIRECTION OUTPUT ;
    USE SIGNAL ;
    SHAPE ABUTMENT ;
    PORT
      LAYER met2 ;
      RECT 331.130 655.100 331.270 655.520 ;
    END
  END rw0_rd_out[42]
  PIN rw0_rd_out[43]
    DIRECTION OUTPUT ;
    USE SIGNAL ;
    SHAPE ABUTMENT ;
    PORT
      LAYER met2 ;
      RECT 338.950 655.100 339.090 655.520 ;
    END
  END rw0_rd_out[43]
  PIN rw0_rd_out[44]
    DIRECTION OUTPUT ;
    USE SIGNAL ;
    SHAPE ABUTMENT ;
    PORT
      LAYER met2 ;
      RECT 346.770 655.100 346.910 655.520 ;
    END
  END rw0_rd_out[44]
  PIN rw0_rd_out[45]
    DIRECTION OUTPUT ;
    USE SIGNAL ;
    SHAPE ABUTMENT ;
    PORT
      LAYER met2 ;
      RECT 354.590 655.100 354.730 655.520 ;
    END
  END rw0_rd_out[45]
  PIN rw0_rd_out[46]
    DIRECTION OUTPUT ;
    USE SIGNAL ;
    SHAPE ABUTMENT ;
    PORT
      LAYER met2 ;
      RECT 362.410 655.100 362.550 655.520 ;
    END
  END rw0_rd_out[46]
  PIN rw0_rd_out[47]
    DIRECTION OUTPUT ;
    USE SIGNAL ;
    SHAPE ABUTMENT ;
    PORT
      LAYER met2 ;
      RECT 370.230 655.100 370.370 655.520 ;
    END
  END rw0_rd_out[47]
  PIN rw0_rd_out[48]
    DIRECTION OUTPUT ;
    USE SIGNAL ;
    SHAPE ABUTMENT ;
    PORT
      LAYER met2 ;
      RECT 378.050 655.100 378.190 655.520 ;
    END
  END rw0_rd_out[48]
  PIN rw0_rd_out[49]
    DIRECTION OUTPUT ;
    USE SIGNAL ;
    SHAPE ABUTMENT ;
    PORT
      LAYER met2 ;
      RECT 385.870 655.100 386.010 655.520 ;
    END
  END rw0_rd_out[49]
  PIN rw0_rd_out[50]
    DIRECTION OUTPUT ;
    USE SIGNAL ;
    SHAPE ABUTMENT ;
    PORT
      LAYER met2 ;
      RECT 393.690 655.100 393.830 655.520 ;
    END
  END rw0_rd_out[50]
  PIN rw0_rd_out[51]
    DIRECTION OUTPUT ;
    USE SIGNAL ;
    SHAPE ABUTMENT ;
    PORT
      LAYER met2 ;
      RECT 401.510 655.100 401.650 655.520 ;
    END
  END rw0_rd_out[51]
  PIN rw0_rd_out[52]
    DIRECTION OUTPUT ;
    USE SIGNAL ;
    SHAPE ABUTMENT ;
    PORT
      LAYER met2 ;
      RECT 409.330 655.100 409.470 655.520 ;
    END
  END rw0_rd_out[52]
  PIN rw0_rd_out[53]
    DIRECTION OUTPUT ;
    USE SIGNAL ;
    SHAPE ABUTMENT ;
    PORT
      LAYER met2 ;
      RECT 417.150 655.100 417.290 655.520 ;
    END
  END rw0_rd_out[53]
  PIN rw0_rd_out[54]
    DIRECTION OUTPUT ;
    USE SIGNAL ;
    SHAPE ABUTMENT ;
    PORT
      LAYER met2 ;
      RECT 424.970 655.100 425.110 655.520 ;
    END
  END rw0_rd_out[54]
  PIN rw0_rd_out[55]
    DIRECTION OUTPUT ;
    USE SIGNAL ;
    SHAPE ABUTMENT ;
    PORT
      LAYER met2 ;
      RECT 432.790 655.100 432.930 655.520 ;
    END
  END rw0_rd_out[55]
  PIN rw0_rd_out[56]
    DIRECTION OUTPUT ;
    USE SIGNAL ;
    SHAPE ABUTMENT ;
    PORT
      LAYER met2 ;
      RECT 440.610 655.100 440.750 655.520 ;
    END
  END rw0_rd_out[56]
  PIN rw0_rd_out[57]
    DIRECTION OUTPUT ;
    USE SIGNAL ;
    SHAPE ABUTMENT ;
    PORT
      LAYER met2 ;
      RECT 448.430 655.100 448.570 655.520 ;
    END
  END rw0_rd_out[57]
  PIN rw0_rd_out[58]
    DIRECTION OUTPUT ;
    USE SIGNAL ;
    SHAPE ABUTMENT ;
    PORT
      LAYER met2 ;
      RECT 456.250 655.100 456.390 655.520 ;
    END
  END rw0_rd_out[58]
  PIN rw0_rd_out[59]
    DIRECTION OUTPUT ;
    USE SIGNAL ;
    SHAPE ABUTMENT ;
    PORT
      LAYER met2 ;
      RECT 464.070 655.100 464.210 655.520 ;
    END
  END rw0_rd_out[59]
  PIN rw0_rd_out[60]
    DIRECTION OUTPUT ;
    USE SIGNAL ;
    SHAPE ABUTMENT ;
    PORT
      LAYER met2 ;
      RECT 471.890 655.100 472.030 655.520 ;
    END
  END rw0_rd_out[60]
  PIN rw0_rd_out[61]
    DIRECTION OUTPUT ;
    USE SIGNAL ;
    SHAPE ABUTMENT ;
    PORT
      LAYER met2 ;
      RECT 479.710 655.100 479.850 655.520 ;
    END
  END rw0_rd_out[61]
  PIN rw0_rd_out[62]
    DIRECTION OUTPUT ;
    USE SIGNAL ;
    SHAPE ABUTMENT ;
    PORT
      LAYER met2 ;
      RECT 487.530 655.100 487.670 655.520 ;
    END
  END rw0_rd_out[62]
  PIN rw0_rd_out[63]
    DIRECTION OUTPUT ;
    USE SIGNAL ;
    SHAPE ABUTMENT ;
    PORT
      LAYER met2 ;
      RECT 495.350 655.100 495.490 655.520 ;
    END
  END rw0_rd_out[63]
  PIN rw0_addr_in[0]
    DIRECTION INPUT ;
    USE SIGNAL ;
    SHAPE ABUTMENT ;
    PORT
      LAYER met3 ;
      RECT 0.000 547.930 0.900 548.230 ;
    END
  END rw0_addr_in[0]
  PIN rw0_addr_in[1]
    DIRECTION INPUT ;
    USE SIGNAL ;
    SHAPE ABUTMENT ;
    PORT
      LAYER met3 ;
      RECT 0.000 564.930 0.900 565.230 ;
    END
  END rw0_addr_in[1]
  PIN rw0_addr_in[2]
    DIRECTION INPUT ;
    USE SIGNAL ;
    SHAPE ABUTMENT ;
    PORT
      LAYER met3 ;
      RECT 0.000 581.930 0.900 582.230 ;
    END
  END rw0_addr_in[2]
  PIN rw0_addr_in[3]
    DIRECTION INPUT ;
    USE SIGNAL ;
    SHAPE ABUTMENT ;
    PORT
      LAYER met3 ;
      RECT 0.000 598.930 0.900 599.230 ;
    END
  END rw0_addr_in[3]
  PIN rw0_addr_in[4]
    DIRECTION INPUT ;
    USE SIGNAL ;
    SHAPE ABUTMENT ;
    PORT
      LAYER met3 ;
      RECT 0.000 615.930 0.900 616.230 ;
    END
  END rw0_addr_in[4]
  PIN rw0_addr_in[5]
    DIRECTION INPUT ;
    USE SIGNAL ;
    SHAPE ABUTMENT ;
    PORT
      LAYER met3 ;
      RECT 558.920 547.930 559.820 548.230 ;
    END
  END rw0_addr_in[5]
  PIN rw0_addr_in[6]
    DIRECTION INPUT ;
    USE SIGNAL ;
    SHAPE ABUTMENT ;
    PORT
      LAYER met3 ;
      RECT 558.920 564.930 559.820 565.230 ;
    END
  END rw0_addr_in[6]
  PIN rw0_addr_in[7]
    DIRECTION INPUT ;
    USE SIGNAL ;
    SHAPE ABUTMENT ;
    PORT
      LAYER met3 ;
      RECT 558.920 581.930 559.820 582.230 ;
    END
  END rw0_addr_in[7]
  PIN rw0_addr_in[8]
    DIRECTION INPUT ;
    USE SIGNAL ;
    SHAPE ABUTMENT ;
    PORT
      LAYER met3 ;
      RECT 558.920 598.930 559.820 599.230 ;
    END
  END rw0_addr_in[8]
  PIN rw0_addr_in[9]
    DIRECTION INPUT ;
    USE SIGNAL ;
    SHAPE ABUTMENT ;
    PORT
      LAYER met3 ;
      RECT 558.920 615.930 559.820 616.230 ;
    END
  END rw0_addr_in[9]
  PIN rw0_we_in
    DIRECTION INPUT ;
    USE SIGNAL ;
    SHAPE ABUTMENT ;
    PORT
      LAYER met2 ;
      RECT 503.170 655.100 503.310 655.520 ;
    END
  END rw0_we_in
  PIN rw0_ce_in
    DIRECTION INPUT ;
    USE SIGNAL ;
    SHAPE ABUTMENT ;
    PORT
      LAYER met2 ;
      RECT 510.990 655.100 511.130 655.520 ;
    END
  END rw0_ce_in
  PIN rw0_clk
    DIRECTION INPUT ;
    USE SIGNAL ;
    SHAPE ABUTMENT ;
    PORT
      LAYER met2 ;
      RECT 518.810 655.100 518.950 655.520 ;
    END
  END rw0_clk
  PIN VSS
    DIRECTION INOUT ;
    USE GROUND ;
    PORT
      LAYER met4 ;
      RECT 2.160 4.080 3.360 651.440 ;
      RECT 13.040 4.080 14.240 651.440 ;
      RECT 23.920 4.080 25.120 651.440 ;
      RECT 34.800 4.080 36.000 651.440 ;
      RECT 45.680 4.080 46.880 651.440 ;
      RECT 56.560 4.080 57.760 651.440 ;
      RECT 67.440 4.080 68.640 651.440 ;
      RECT 78.320 4.080 79.520 651.440 ;
      RECT 89.200 4.080 90.400 651.440 ;
      RECT 100.080 4.080 101.280 651.440 ;
      RECT 110.960 4.080 112.160 651.440 ;
      RECT 121.840 4.080 123.040 651.440 ;
      RECT 132.720 4.080 133.920 651.440 ;
      RECT 143.600 4.080 144.800 651.440 ;
      RECT 154.480 4.080 155.680 651.440 ;
      RECT 165.360 4.080 166.560 651.440 ;
      RECT 176.240 4.080 177.440 651.440 ;
      RECT 187.120 4.080 188.320 651.440 ;
      RECT 198.000 4.080 199.200 651.440 ;
      RECT 208.880 4.080 210.080 651.440 ;
      RECT 219.760 4.080 220.960 651.440 ;
      RECT 230.640 4.080 231.840 651.440 ;
      RECT 241.520 4.080 242.720 651.440 ;
      RECT 252.400 4.080 253.600 651.440 ;
      RECT 263.280 4.080 264.480 651.440 ;
      RECT 274.160 4.080 275.360 651.440 ;
      RECT 285.040 4.080 286.240 651.440 ;
      RECT 295.920 4.080 297.120 651.440 ;
      RECT 306.800 4.080 308.000 651.440 ;
      RECT 317.680 4.080 318.880 651.440 ;
      RECT 328.560 4.080 329.760 651.440 ;
      RECT 339.440 4.080 340.640 651.440 ;
      RECT 350.320 4.080 351.520 651.440 ;
      RECT 361.200 4.080 362.400 651.440 ;
      RECT 372.080 4.080 373.280 651.440 ;
      RECT 382.960 4.080 384.160 651.440 ;
      RECT 393.840 4.080 395.040 651.440 ;
      RECT 404.720 4.080 405.920 651.440 ;
      RECT 415.600 4.080 416.800 651.440 ;
      RECT 426.480 4.080 427.680 651.440 ;
      RECT 437.360 4.080 438.560 651.440 ;
      RECT 448.240 4.080 449.440 651.440 ;
      RECT 459.120 4.080 460.320 651.440 ;
      RECT 470.000 4.080 471.200 651.440 ;
      RECT 480.880 4.080 482.080 651.440 ;
      RECT 491.760 4.080 492.960 651.440 ;
      RECT 502.640 4.080 503.840 651.440 ;
      RECT 513.520 4.080 514.720 651.440 ;
      RECT 524.400 4.080 525.600 651.440 ;
      RECT 535.280 4.080 536.480 651.440 ;
      RECT 546.160 4.080 547.360 651.440 ;
      RECT 557.040 4.080 558.240 651.440 ;
    END
  END VSS
  PIN VDD
    DIRECTION INOUT ;
    USE POWER ;
    PORT
      LAYER met4 ;
      RECT 2.160 4.080 3.360 651.440 ;
      RECT 13.040 4.080 14.240 651.440 ;
      RECT 23.920 4.080 25.120 651.440 ;
      RECT 34.800 4.080 36.000 651.440 ;
      RECT 45.680 4.080 46.880 651.440 ;
      RECT 56.560 4.080 57.760 651.440 ;
      RECT 67.440 4.080 68.640 651.440 ;
      RECT 78.320 4.080 79.520 651.440 ;
      RECT 89.200 4.080 90.400 651.440 ;
      RECT 100.080 4.080 101.280 651.440 ;
      RECT 110.960 4.080 112.160 651.440 ;
      RECT 121.840 4.080 123.040 651.440 ;
      RECT 132.720 4.080 133.920 651.440 ;
      RECT 143.600 4.080 144.800 651.440 ;
      RECT 154.480 4.080 155.680 651.440 ;
      RECT 165.360 4.080 166.560 651.440 ;
      RECT 176.240 4.080 177.440 651.440 ;
      RECT 187.120 4.080 188.320 651.440 ;
      RECT 198.000 4.080 199.200 651.440 ;
      RECT 208.880 4.080 210.080 651.440 ;
      RECT 219.760 4.080 220.960 651.440 ;
      RECT 230.640 4.080 231.840 651.440 ;
      RECT 241.520 4.080 242.720 651.440 ;
      RECT 252.400 4.080 253.600 651.440 ;
      RECT 263.280 4.080 264.480 651.440 ;
      RECT 274.160 4.080 275.360 651.440 ;
      RECT 285.040 4.080 286.240 651.440 ;
      RECT 295.920 4.080 297.120 651.440 ;
      RECT 306.800 4.080 308.000 651.440 ;
      RECT 317.680 4.080 318.880 651.440 ;
      RECT 328.560 4.080 329.760 651.440 ;
      RECT 339.440 4.080 340.640 651.440 ;
      RECT 350.320 4.080 351.520 651.440 ;
      RECT 361.200 4.080 362.400 651.440 ;
      RECT 372.080 4.080 373.280 651.440 ;
      RECT 382.960 4.080 384.160 651.440 ;
      RECT 393.840 4.080 395.040 651.440 ;
      RECT 404.720 4.080 405.920 651.440 ;
      RECT 415.600 4.080 416.800 651.440 ;
      RECT 426.480 4.080 427.680 651.440 ;
      RECT 437.360 4.080 438.560 651.440 ;
      RECT 448.240 4.080 449.440 651.440 ;
      RECT 459.120 4.080 460.320 651.440 ;
      RECT 470.000 4.080 471.200 651.440 ;
      RECT 480.880 4.080 482.080 651.440 ;
      RECT 491.760 4.080 492.960 651.440 ;
      RECT 502.640 4.080 503.840 651.440 ;
      RECT 513.520 4.080 514.720 651.440 ;
      RECT 524.400 4.080 525.600 651.440 ;
      RECT 535.280 4.080 536.480 651.440 ;
      RECT 546.160 4.080 547.360 651.440 ;
      RECT 557.040 4.080 558.240 651.440 ;
    END
  END VDD
  OBS
    LAYER met1 ;
    RECT 0 0 559.820 655.520 ;
    LAYER met2 ;
    RECT 0 0 559.820 655.520 ;
    LAYER met3 ;
    RECT 0 0 559.820 655.520 ;
    LAYER met4 ;
    RECT 0 0 559.820 655.520 ;
  END
END fakeram_64x1024_1rw

END LIBRARY
